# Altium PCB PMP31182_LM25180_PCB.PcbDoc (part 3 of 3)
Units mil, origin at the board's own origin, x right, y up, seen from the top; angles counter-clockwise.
Board outline 4922 x 2266 mil, 4 copper layers (Top Layer, Signal Layer 1, Signal Layer 2, Bottom Layer), stack 77.9 mil thick; 166 components, 96 nets, 525 pads, 505 vias.

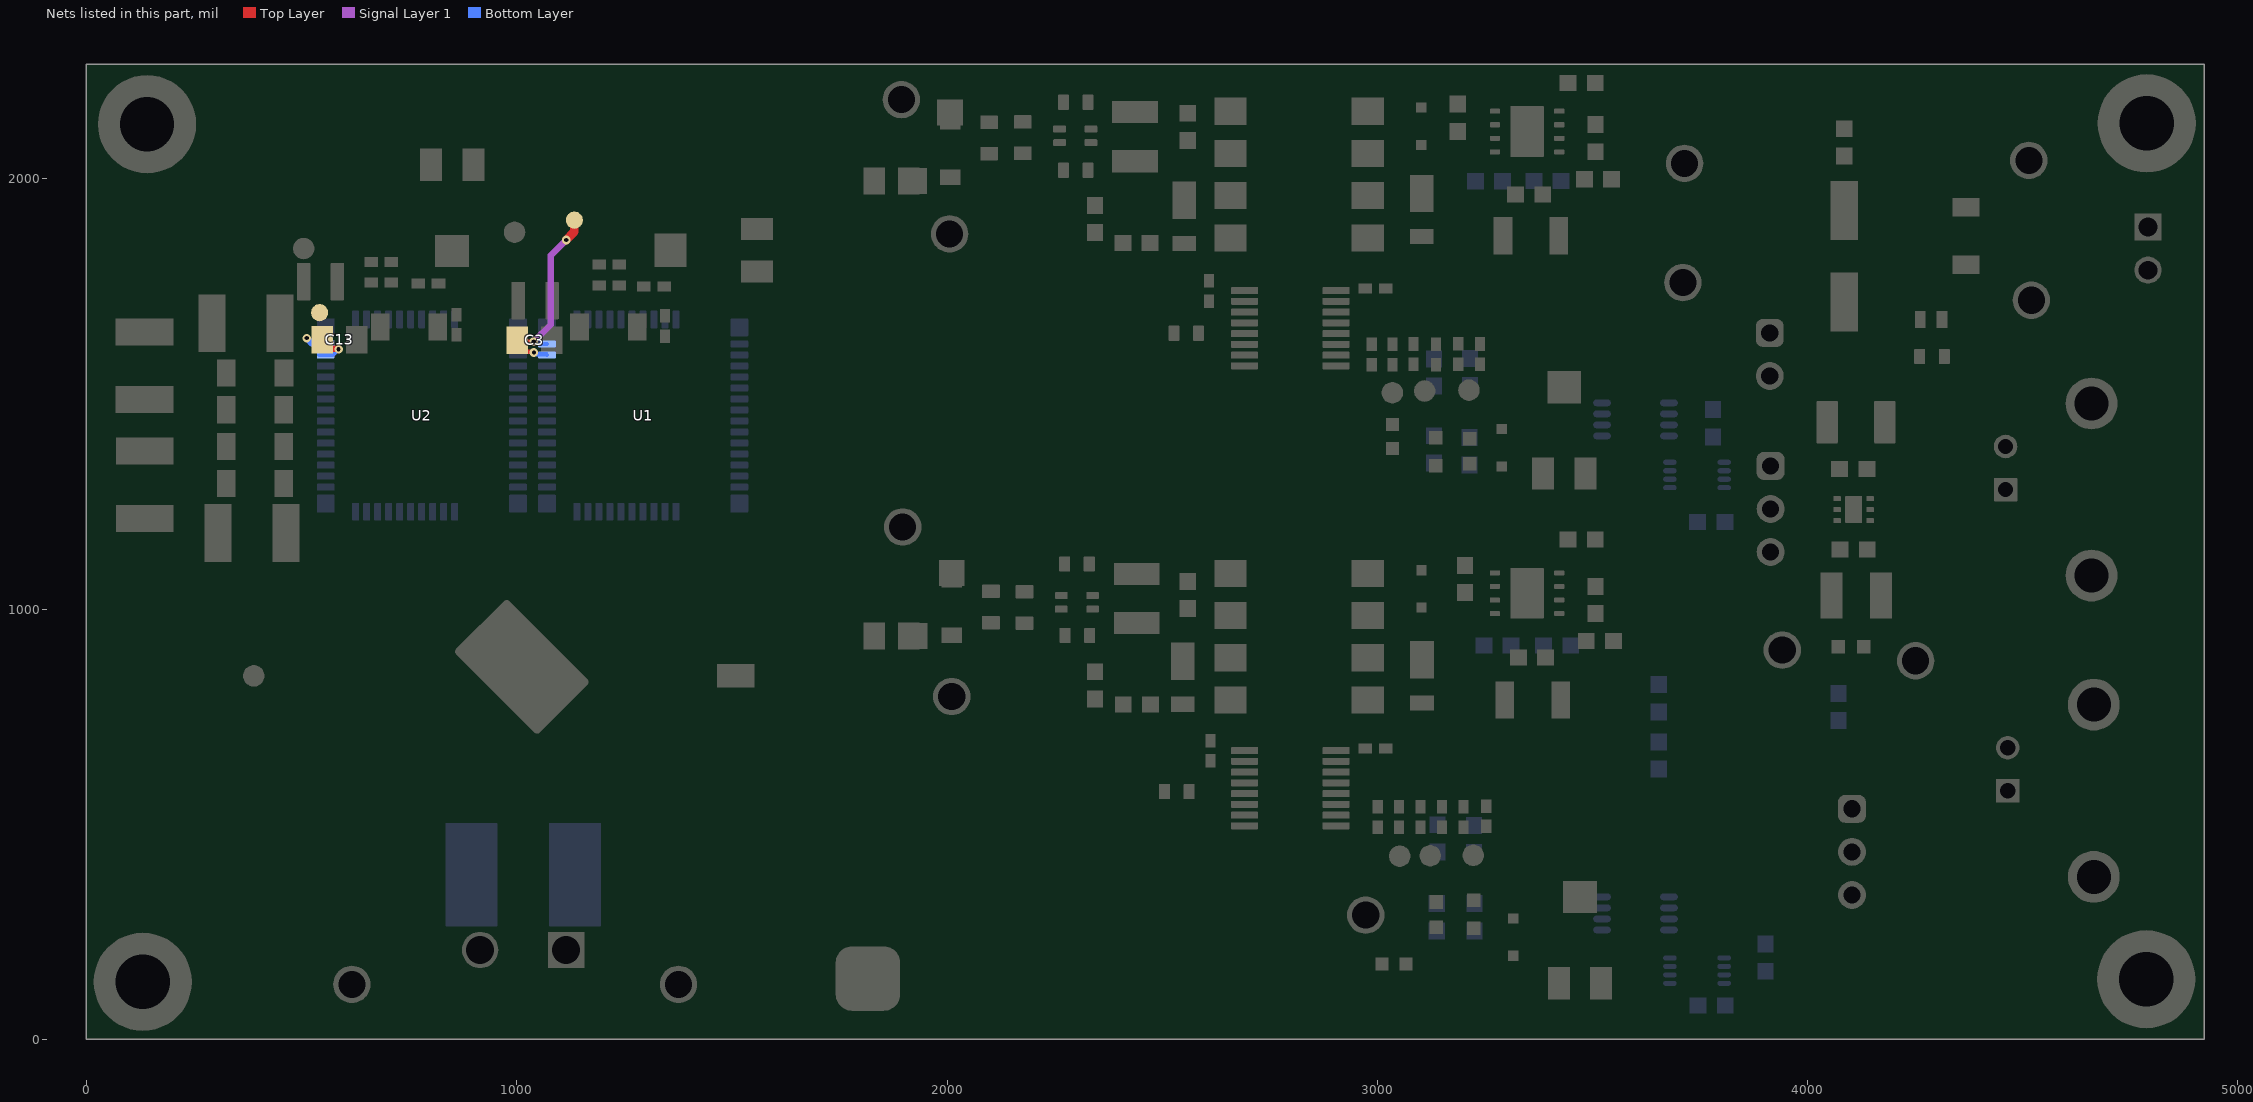
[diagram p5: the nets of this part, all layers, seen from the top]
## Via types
v1: diameter 20, hole 10, Top Layer to Bottom Layer, tented both sides, 491 vias
v2: diameter 19.68, hole 7.87, Top Layer to Bottom Layer, 10 vias
v3: diameter 47.24, hole 31.5, Top Layer to Bottom Layer, 4 vias

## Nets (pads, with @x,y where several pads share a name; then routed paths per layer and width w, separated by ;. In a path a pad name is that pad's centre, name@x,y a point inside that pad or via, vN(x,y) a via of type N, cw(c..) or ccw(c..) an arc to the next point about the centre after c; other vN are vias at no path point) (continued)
VNEG_H: C3.2 pad.1@1134,1904 U1.40 U1.41 | length 477.5
  Top Layer w10: C3.2@1001,1625 1001,1618.5 1021,1598.5 1035.25,1598.5 1037.29,1596.46 v1(1040,1596.46) ; C3.2@1004,1622 v1(1039.76,1622)
  Top Layer w20: v1(1115,1858) 1134,1877 pad.1@1134,1904
  Signal Layer 1 w15: v1(1039.76,1622) 1079,1661.24 1079,1822 v1(1115,1858)
  Bottom Layer w10: v1(1039.76,1622) 1052.1,1622 1057.78,1616.32 U1.41@1070.58,1616.32 ; v1(1040,1596.46) 1042.71,1596.46 1046.91,1592.26 1069.04,1592.26 U1.40@1070.58,1590.73
VNEG_L: C13.2 pad.1@542,1689 U2.40 U2.41 | length 147.3
  Top Layer w15: C13.2@549,1624 568,1605 v1@587,1605
  Bottom Layer w10: U2.40@541.28,1590.73 U2.40@556.15,1590.73 572.73,1590.73 v1@587,1605
  Bottom Layer w15: v1(512,1630) 525.69,1616.32 U2.41@556.15,1616.32
  other v1: 586,1604
pads on no net: J1.3 J1.4 J4.3 J4.4 R2.3 R5.3 R33.3 R37.3 SH-J1.0 SH-J2.0 SH-J3.0 T1.2 T1.3 T2.2 T2.3 T3.5 T3.7@4107,1213.63 T3.7@4107,1249.06 U5.9@3348,1007.28 U5.9@3348,1066.72 U6.9@3348,2080.28 U6.9@3348,2139.72

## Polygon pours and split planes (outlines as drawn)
GND_LV on Bottom Layer "Signal Layer 1-GND_LV" (solid, pour order 147): 3045,2193 3045,2196 3091,2238 3583,2238 3787,2238 3833,2192 3832,2191 3832,1609 3868,1574 4859,1574 4859,415 4466,22 3172,22 3110,84 3110,269 3005,374 3005,441 2900,441 2898,439 2898,490 2996.53,490 3008,501.47 3008,1242 2937,1242 2936,1241 2934,1243 2934,1310 2987,1310 3008,1331 3008,1487 2977,1518 2977,1743 3045,1811
GND_HV on Bottom Layer "GND_HV_L04_P000" (solid, remove dead copper, pour order 0): 900,1639 893,1646 786,1646 652,1646 580,1574 470,1574 450,1554 450,1154 470,1134 820,1134 900,1214
SW on Bottom Layer "SW_L04_P004" (solid, remove dead copper, pour order 4): 970.29,1674.3 970.29,1165.3 895,1090 895,1069 905,1059 1221,1059 1238.29,1076.29 1238.29,1175.29 1260.89,1197.89 1371,1198 1380,1207 1380,1246 1240,1386 1240,1450.84 1380,1590.84 1380,1636 1370,1646 1131,1646 1100,1615 1100,1583 1091,1574 1032,1574 1024,1582 1024,1673.77 1013.76,1684 980,1684
HVBUS on Bottom Layer "HVBUS_L04_P016" (solid, remove dead copper, pour order 16): 1540,1672.95 1540,1214 1470,1214 1450,1234 1450,1654 1473,1677 1535.95,1677
SW on Signal Layer 2 "SW_L03_P002" (solid, remove dead copper, pour order 2): 2691,653 2713,631 2713,484 2700,471 2475.05,471 1607,1289.18 1607,1637.45 1530.46,1714 1474,1714 1354,1594 984,1594 973,1605 973,1865 1022,1914 1530,1914 1960,1484 2586.56,857.45 2586.56,757.44
HVBUS on Signal Layer 2 "HVBUS_L03_P054" (solid, remove dead copper, pour order 54): 376,22 317.88,64 317.88,192.12 79.88,430.12 79.88,1709.88 95,1725 342,1725 476,1591 476,1530 1406.59,1530 1491.2,1635.68 1531.32,1635.68 1538.88,1628.12 1538.88,1226.88 1525,1213 935,1213 758.88,1036.88 758.88,470.68 763.88,470.68 814.88,419.68 953.88,419.68 953.88,417.99 977.88,393.99 977.88,60 928,22
GND_LV on Signal Layer 2 "Signal Layer 1-GND_LV" (solid, pour order 146): 4759,1574 4859,1474 4859,415 4466,22 3172,22 3110,84 3110,269 3005,374 3005,441 2900,441 2898,439 2898,490 2996.53,490 3008,501.47 3008,1242 2937,1242 2936,1241 2934,1243 2934,1310 2987,1310 3008,1331 3008,1493 2977,1524 2977,1729 3045,1797 3045,2193 3045,2196 3091,2238 3583,2238 3787,2238 3833,2192 3832,2191 3832,1609 3868,1574
GND_HV on Signal Layer 2 "GND_HV_L03_P096" (solid, remove dead copper, pour order 96): 484,1655.47 484,2146 575,2237 2065,2237 2187,2237 2679,1745 2679,1579.01 2643.99,1544 2037,1544 1627,1954 957,1954 920,1917 920,1620 894,1594 545.48,1594
5V on Signal Layer 2 "5V_L03_P136" (solid, pour order 136): 4375.35,797.4 4114.35,797.4 4114.35,944.4 4118.35,948.4 4118.35,1110.4 4118.35,1156.4 4148.35,1186.4 4171.35,1186.4 4171.35,1223.4 4147.69,1247.06 4147.69,1251.4 4137.35,1251.4 4135.35,1253.4 4135.35,1263.4 4153.35,1263.4 4375.35,1263.4
GND_LV on Signal Layer 1 "Signal Layer 1-GND_LV" (solid, pour order 134): 4770,1575 4859,1486 4859,416 4466,23 3172,23 3110,85 3110,270 3005,375 3005,442 2900,442 2898,440 2898,491 2996.53,491 3008,502.47 3008,1243 2937,1243 2936,1242 2934,1244 2934,1311 2987,1311 3008,1332 3008,1488 2977,1519 2977,1744 3045,1812 3045,2194 3045,2197 3091,2239 3583,2239 3787,2239 3833,2193 3832,2192 3832,1610 3868,1575
GND_HV on Signal Layer 1 "GND_HV_L02_P008" (solid, remove dead copper, pour order 8): 1748,312 1748,313 1706,356 1706,1084 1606,1184 1450,1184 1420,1214 1420,1544 1390,1574 500,1574 481,1593 481,1763 470,1774 320,1774 310,1764 310,1674 283,1647 97,1647 70,1620 70,1064 90,1044 730,1044 888,1202 1251,1202 1300,1153 1300,561 1300.32,560.76 1300.32,560.32 1247,507 1099,507 1073,481 1073,50.87 1103.87,20 1922,20 1923,19 1955,51 1955,260 1903,312
GND_HV on Top Layer "Top Layer-GND_HV" (solid, pour order 152): 924,2070 921,2073 877,2073 874,2070 874,1991 cw(c865.01,1990.99) 865,1982 762.87,1982 749,1968.13 749,1778.65 741.06,1770.72 701,1770.72 696.72,1770.72 693,1767 693,1740 704,1729 719,1714 719,1698 712,1691 712,1618 656,1618 653,1621 653,1655 651,1657 607,1657 603,1653 603,1599 608,1594 894,1594 900,1600 900,1644 890,1654 845,1654 840,1659 840,1686 749,1686 737,1698 737,1715.41 787,1745.19 787,1948 911,1948 ccw(c911.01,1960.99) 924,1961
SW on Top Layer "Top Layer-No Net" (solid, pour order 144): 1301,1685 1299,1687 1292.24,1687 1259,1687 cw(c1258.98,1695.8) 1250.18,1695.82 1250.18,1731.5 1257,1738 1308.8,1738 1311,1741 1311,1761.81 1306,1766 1226.81,1766 1223,1762.18 1223,1740 1233.18,1729.82 1233.17,1693.57 1233.17,1682.07 1223,1671.9 1185,1671.9 1177.05,1663.95 1176.73,1618.6 1172,1615.42 1110.58,1615.42 1106.12,1619.88 1106.11,1656.49 1098.12,1669.79 1098.12,1759.88 1096.19,1761.81 1068.81,1761.81 1067,1760 1067,1670.21 1056.12,1656.65 1056.12,1595.32 1069.33,1588.58 1351.95,1588.58 ccw(c1351.95,1596.8) 1360.18,1596.8 1360.18,1646.58 1355.14,1651 1312.11,1651 1301,1661
SW on Top Layer "SW_L01_P145" (solid, pour order 145): 1608.82,1549.61 1644,1584.79 1824.3,1584.7 2286,1123 2286,1088 2271.51,1073.51 2271.51,1043.49 2280,1035 2280,1025 2083,1025 2056.91,1051.09 1889.91,1051.09 1608.82,1332.18
GND_HV on Top Layer "GND_HV_L01_P082" (solid, remove dead copper, pour order 82): 418,1783 426.8,1794 471,1794 481,1784 481,1667 481,1593 550,1524 1309,1524 1391,1442 1391,1216 1446,1161 1629,1161 1705,1085 1705,356 1748,312 1903,312 1955,260 1955,51 1923,19 1922,20 1705,20 1104.63,20 1074,56.55 1074,482 1099,507 1247,507 1299,559 1300,561 1300,1184.41 1254.37,1230.04 916.04,1230.04 790,1104 418,1104
ISO_15V_H on Top Layer "ISO_15V_H_L01_P116" (solid, pour order 116): 1886,970 1898,982 2067.35,982 2227,982 2252,1007 2277,1007 2280,1004 2280,982 2280,959 2287,952 2287,751 2265,729 1906,729 1886,749
GND_LV on Top Layer "GND_LV_L01_P149" (solid, pour order 149): 3900,1495 3900,745 3994,651 4518,651 4534,702 4534,745 4534,1454 4489,1499 3903,1499
NetC11_2 on Top Layer "NETC11_2_L01_P148" (solid, pour order 148): 647,1845 660,1858 660,2076 716,2132 1523,2132 1692,1963 1855,1963 1855,2026 1757,2026 1559,2224 645,2224 585,2164 585,1857 597,1845
NetD2_2 on Top Layer "NETD2_2_L01_P140" (solid, pour order 140): 2453,764 2459,758 2690.27,758 2696,764.3 2696,908 2686,918 2632,918 2622,908 2622,806 2621,806 2612,797 2461.7,797 2453,788
NetD7_2 on Top Layer "NETD7_2_L01_P141" (solid, pour order 141): 2611,1869 2622,1879 2622,1982 2632,1992 2686,1992 2696,1982 2696,1841.5 2687.36,1832 2459,1832 2453,1838 2453,1865.46 2456.54,1869
GND_LV on Top Layer "GND_LV_L01_P139" (solid, pour order 139): 3117.25,639.25 3126,648 3126,695 3117.75,703.25 3019,703.25 3004,688.25 3004,662.22 2996.03,654.25 2925,654.25 2925,639.25
GND_LV on Top Layer "GND_LV_L01_P138" (solid, pour order 138): 3104,1708 3114,1718 3114,1759 3101,1772 3019,1772 3004,1757 3004,1730.97 2996.03,1723 2925,1723 2925,1708
GND_LV on Top Layer "Top Layer-GND_LV" (solid, pour order 114): 3939.55,2067.55 3965,2094 4250,2094 4489,1855 4846,1855 4858,1867 4858,1956 4827.7,1986.3 4674,1986.3 4637.3,2023 4638,2023 4638,2222 4621.71,2238.29 3934.27,2237.73 3934,2238 3570,2238 3553,2221 3553,2039 3541,2027 3524,2027 3519,2022 3519,1976.46 3507.54,1965 3450.19,1965 3387,2028.19 3387,2075 3379,2083 3318,2083 3309,2074 3309,2016 3314,2011 3348,2011 3364,1994.46 3364,1840 3381,1823 3493,1823 3512,1842 3583,1913 3925,1913 3939.55,1927.55
15V on Top Layer "15V_L01_P104" (solid, pour order 104): 4846,1821 4859,1807 4859,1576 4846,1563 4312,1563 4300,1575 4300,1812 4309,1821
5V on Top Layer "5V_L01_P118" (solid, pour order 118): 4345,1263 4375,1233 4376,1231 4376,822 4351,797 4136,797 4115,818 4115,944 4144,973 4144,1085 4119,1110 4119,1156 4149,1186 4172,1186 4172,1227.34 4148.34,1251 4138,1251 4136,1253 4136,1263
ISO_15V_H_B on Top Layer "ISO_15V_H_B_L01_P115" (solid, pour order 115): 2318.64,847.36 2332,834 2589,834 2589,1021 2553,1021 2525,993 2388,993 2374,1007 2326,1007 2324,1005 2324,954.6 2319.2,949.8
ISO_RET_H_B on Top Layer "ISO_RET_H_B_L01_P117" (solid, pour order 117): 2688,1146 2698,1136 2698,951 2691,944 2633,944 2622,955 2622,1045 2374,1045 2352,1023 2331,1023 2324,1030 2324,1078 2318,1084 2318,1137 2327,1146
ISO_15V_L on Top Layer "ISO_15V_L_L01_P113" (solid, pour order 113): 2248,2092 2231,2075 2080,2075 2031,2026 1886,2026 1886,1845 1912,1819 2274,1819 2284,1829 2284,2030 2276.5,2037.5 2276.5,2038 2276.5,2079.5 2276.5,2089.5 2274,2092
GND_HV on Top Layer "GND_HV_L01_P112" (solid, pour order 112): 2271,2108 2276,2113 2276,2155 2283,2162 2283,2194 2283,2238 1734,2238 1734,2184 1803,2115 2076,2115 2241,2115 2248,2108
ISO_15V_L_B on Top Layer "ISO_15V_L_B_L01_P111" (solid, pour order 111): 2315,1932 2328,1919 2574,1919 2578,1923 2578,2104 2573,2109 2541,2109 2499,2067 2384,2067 2359,2092 2322,2092 2319,2089 2319,2046 2315,2037.2
GND_LV on Top Layer "GND_LV_L01_P110" (solid, pour order 110): 3456,2244.5 3463,2237.5 3463,2237 3463,2163 3451,2151 3309,2151 3309,2235 3318.5,2244.5
GND_LV on Top Layer "GND_LV_L01_P109" (solid, pour order 109): 3453,1078 3463,1088 3463,1202 3456,1209 3318,1209 3309,1199 3309,1083 3314,1078
GND_LV on Top Layer "GND_LV_L01_P108" (solid, pour order 108): 3370,782 3406,746 3406,745 3557,745 3586,774 3586,946 3581,951 3535,951 3529,945 3529,890 3522,883 3424,883 3424,942 3387,979 3387,998 3383,1003 3314,1003 3309,997 3309,963.52 3316.23,956.29 3340.71,956.29 3370,927
NetD5_2 on Top Layer "NETD5_2_L01_P107" (solid, pour order 107): 3278,1078 3284,1084 3285,1085 3285,1203 3277,1211 2961,1211 2958,1211 2940,1193 2940,1069 2940,1064 2953,1051 3103,1051 3133.5,1078
NetD10_2 on Top Layer "NETD10_2_L01_P106" (solid, pour order 106): 2940,2130.5 2945,2125.5 3109,2125.5 3135,2151.5 3280,2151.5 3285,2156.5 3285,2234.5 3275,2244.5 2953,2244.5 2940,2231.5
15V_F on Top Layer "Top Layer-15V_F" (solid, pour order 105): 3248,987.85 3263.35,1015 3285,1015 3285,1027 3284,1028 3248.32,1028 3213,978.5 3166.5,978.5 3152,964 3152,822 2939,822 2936,819 2936,741 2955,722 3143,722 3395,470 3790,470 3817,505.67 3817,1580 3818,1580 3850,1610 3939,1610 3988,1561 4264,1561 4275.44,1572.44 4275.44,1797.56 4268,1805 3633,1805 3591,1805 3557,1771 3362,1771 3341,1792 3341,1986 3331.44,1995.56 3238,1995.56 3238,2061 3266,2089 3283,2089 3285,2091 3285,2100 3284,2101 3278,2101 3244,2101 3198,2055 3168,2055 3156,2043 3156,1902 3150,1896 2942,1896 2932,1886 2932,1804 2944,1792 3127,1792 3309,1610 3574,1610 3623,1561 3623,939 3624,938 3622.73,936.73 3622.73,747.01 3564.72,689 3399.5,689 3348,740.5 3348,908 3343,913 3259.97,913 3248,926.68
VNEG_L on Top Layer "VNEG_L_L01_P097" (solid, remove dead copper, pour order 97): 579,1594 586,1601 586,1615 575,1626 575,1674 567,1682 567,1698 554,1711 536,1711 500,1675 500,1600 506,1594
SW on Top Layer "SW_L01_P088" (solid, remove dead copper, pour order 88): 975,1170 810,1005 810,644 830,624 1210,624 1238.29,652.29 1238.29,1159.71 1228,1170
HVBUS on Top Layer "HVBUS_L01_P032" (solid, remove dead copper, pour order 32): 60,462 60,1234 70,1244 250,1244 270,1264 270,1584 250,1604 70,1604 60,1614 60,1720 74,1734 340,1734 350,1724 350,1062 368,1044 700,1044 740.14,1003.86 740.14,559 793,508 935,508 959,484 959,59 921,21 343.14,21 308,66.61 308,214
GND_HV on Top Layer "GND_HV_L01_P030" (solid, remove dead copper, pour order 30): 70,1524 60,1514 60,1344 70,1334 201,1334 208,1341 208,1514 198,1524
ISO_RET_L_B on Top Layer "ISO_RET_L_B_L01_P028" (solid, pour order 28): 2320,2161 2315,2166 2315,2229 2325,2239 2684,2239 2696,2227 2696,2035 2689,2028 2628,2028 2622,2034 2622,2126 2615,2133 2541,2133 2537,2129 2369,2129 2348,2108 2325,2108 2320,2113

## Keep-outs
Keep-Out Layer:
  lines w10: 2136.71,2261 2141.71,2266 4922,2266 4922,0 3006,0
  text ".Layer_Name" at 502,-792.77 h30

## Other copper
Signal Layer 1:
  pour cut-out: 267,1132.33 267,1164.5 244.91,1178 130.3,1178 111.84,1162.73 111.84,1135 133.17,1119 162.28,1119 247,1119
  pour cut-out: 266,1227.07 306,1227.07 316,1241 316,1578.62 302.49,1595.51 269.25,1595.51 257,1579.17 257,1526.56 257,1241.86
Signal Layer 2:
  pour cut-out: 536,1336 546,1346 546,1411.23 538.99,1420 481.25,1420 473,1409 473,1348.18 480.88,1336
  pour cut-out: 534,1125 546,1137 546,1202.23 537.39,1213 482.75,1213 472,1198.67 472,1140.73 482.18,1125
  pour cut-out: 534,1227 547,1240 547,1302.98 537.39,1315 482.75,1315 473,1302 473,1241.18 482.18,1227
  pour cut-out: 536,1443 547,1454 547,1516.98 538.99,1527 481.25,1527 472,1514.67 472,1456.73 480.88,1443
  pour cut-out: 108,1399 119,1388 200.75,1388 212,1397 212,1454.75 197,1466 124.73,1466 108,1455.18

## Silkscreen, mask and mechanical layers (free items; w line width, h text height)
Top Overlay:
  lines w10: 556,1866 556,1884 557,1885 ; 577,1885 557,1885 ; 623,1819 557,1885 ; 3085,1652 3085,1689 3159,1763 ; 3140,1763 3158,1763 ; 3159,1746 3159,1760
  text "-" at 4727.87,1978 h150 r90
  text "+" at 4658,1621.5 h150
  text "PWM BOT" at 4349.35,1231 h60 r90
  text "PWM TOP" at 4352.02,477 h60 r90
  text "Load_GND" at 1694,241.99 h60
  text "Max DC Input:  / 520 V/25 A" at 804,44 h60
  text "PMP31182_LM25180-Q1" at 3571,16 h60
Bottom Overlay:
  text "Max DC Input:  / 520 V/25 A" at 1371,45 h30
Top Paste:
  text ".Layer_Name" at 5093,3542.51 h30
Bottom Paste:
  text ".Layer_Name" at 5093,3542.51 h30
Top Solder:
  text ".Layer_Name" at 5093,3542.51 h30
Bottom Solder:
  text ".Layer_Name" at 5093,3542.51 h30
M1 Board Outline:
  the board outline again, w15
  text ".Layer_Name" at 502,-792.77 h30
M2 Board Dimensions:
  rectangle: -70,-219.27 55,-94.27
  rectangle: 50,-344.77 425,-219.77
  lines w7: -75,-94.77 -75,-344.77 925,-344.77 925,-94.77 ; -70,-219.27 930,-219.27 ; -70,-94.27 930,-94.27 ; 50,-344.77 50,-94.77 ; 175,-344.77 175,-94.77 ; 425,-344.77 425,-94.77 ; 675,-344.77 675,-94.77
  lines w10: -14.57,3 2986.43,3 ; 0,604 0,2266 4922,2266 4922,0 3624,0 3619,5
  text ".Layer_Name" at 502,-792.77 h30
M3 3D STEP Top:
  lines w10: 0,9 0,2266 4922,2266 4922,9 0,9
  text ".Layer_Name" at 502,-792.77 h30
M4 3D STEP Bottom:
  lines w10: 588.72,2260 583.69,2256.46 208.56,2256.46 0,2139.46 0,0 4922,0 4922,2266 2136.21,2266 2130.21,2260 ; 524,1188 1550,1188 1550,1730 524,1730 524,1188
M5 Assembly Top:
  lines w10: -367,-864.44 6233,-864.44 ; -367,-661.11 6235,-661.11 ; -367,-457.77 -367,-1067.77 3638,-1067.77 6235,-1067.77 6235,-457.77 -366.5,-457.77 -366.5,-1067.77 ; 2098,-1067.77 2098,-457.77 ; 3365,-661.11 3365,-457.77 ; 4205,-661.11 4205,-457.77 ; 4224.5,3267.5 5800,3267.5 ; 4827,-1074.27 4827,-871.44
  text "PCB VIEWED FROM TOP SIDE" at 4287.5,3745.33 h30
  text "IGNORE ->" at 4287.5,3542.51 h30
  text "PLOT NAME =" at 4287.5,3336.67 h30
  text "COMPONENTS MARKED 'DNP' SHOULD NOT BE POPULATED." at 1078.5,-252.77 h30
  text "ASSEMBLY VARIANT:" at 1078,-368.27 h30
  text ".VariantName" at 2114,-368.27 h30
  text "BOARD #:" at 2173,-589.94 h30
  text ".PRJ_Number" at 2718.5,-589.94 h30
  text "REV:" at 3563,-589.94 h30
  text ".PCB_Rev" at 3854.5,-589.94 h30
  text "SVN REV:" at 4401,-589.94 h30
  text ".VersionControl_RevNumber" at 4907,-589.94 h30
  text ".plot_File_Name" at 502,-998.61 h30
  text "GENERATED    :" at 2175,-998.61 h30
  text ".Print_Date" at 3044.5,-998.61 h30
  text ".Print_Time" at 3773.5,-998.61 h30
  text "TEXAS INSTRUMENTS" at 5038,-998.61 h30
M6 Assembly Bottom:
  lines w10: -367.5,-661.61 6234.5,-661.61 ; -365.5,-864.94 6234.5,-864.94 ; 1662.5,-661.61 1662.5,-458.27 ; 2502.5,-661.61 2502.5,-458.27 ; 3769.5,-1068.27 3769.5,-458.27 ; 4658.5,-1068.27 6234,-1068.27 6234,-458.27 -367.5,-458.27 -367.5,-1068.27 2229.5,-1068.27 6234.5,-1068.27 6234.5,-458.27 ; 5631.5,3260.5 5631.5,3463.33
  text ".VersionControl_RevNumber" at 5551.5,3744.83 h30
  text "TEXAS INSTRUMENTS" at 5420.5,3336.17 h30
  text "COMPONENTS MARKED 'DNP' SHOULD NOT BE POPULATED." at 6724,-256.27 h30
  text ".VariantName" at 5680,-372.27 h30
  text "ASSEMBLY VARIANT:" at 6719,-372.27 h30
  text "SVN REV:" at 1466.5,-590.44 h30
  text ".PCB_Rev" at 2013,-590.44 h30
  text "REV:" at 2304.5,-590.44 h30
  text ".PRJ_Number" at 3149,-590.44 h30
  text "BOARD #:" at 3694.5,-590.44 h30
  text "PCB VIEWED FROM BOTTOM SIDE" at 6171,-590.44 h30
  text "IGNORE ->" at 2472.85,-792.77 h30
  text ".Print_Time" at 2094,-999.11 h30
  text ".Print_Date" at 2823,-999.11 h30
  text "GENERATED    :" at 3692.5,-999.11 h30
  text ".plot_File_Name" at 5365.5,-999.11 h30
  text "PLOT NAME =" at 6171,-999.11 h30
M9 Title Sheet:
  drawing of 57 lines, arcs and shapes, not listed
  text "1" at 664.84,8102.23 h30
  text "2" at 3160.5,8102.23 h30
  text "3" at 5649.84,8102.23 h30
  text "4" at 8156.51,8102.23 h30
  text "5" at 10655.5,8102.23 h30
  text "6" at 13160.5,8102.23 h30
  text "A" at -491.5,6959.23 h30
  text "A" at 14308.5,6959.23 h30
  text "B" at -491.5,4579.23 h30
  text "B" at 14308.5,4579.23 h30
  text "1" at 5255.84,3137.5 h30
  text "C" at 14308.5,2204.23 h30
  text "PROJECT TITLE:" at 11268.5,343.23 h30
  text "LMG342xRx0" at 11318.5,209.9 h30
  text "DESIGNED FOR:" at 11268.5,42.23 h30
  text ".PRJ_Customer" at 11318.5,-97.77 h30
  text "D" at -491.5,-165.77 h30
  text "D" at 14308.5,-165.77 h30
  text "FILE NAME:" at 11268.5,-257.77 h30
  text ".PCB_File_Name_No_Path" at 11318.5,-377.77 h30
  text "Texas Instruments (TI) and/or its licensors do not warrant the accuracy or completeness of this specification" at 6299,-539.61 h30
  text "ENGINEER:" at 11268.5,-547.77 h30
  text "LAYOUT BY:" at 12773.5,-547.77 h30
  text "or any information contained therein. TI and/or its licensors do not warrant that this design will meet" at 6254.02,-652.28 h30
  text "Rui Gao" at 11318.5,-702.77 h30
  text "Rui Gao" at 12824,-702.77 h30
  text "the specifications, will be suitable for your application or fit for any particular purpose, or will operate in" at 6254.02,-764.94 h30
  text ".Layer_Name" at 502,-792.77 h30
  text "ALTIUM DESIGNER VERSION:" at 12773.5,-857.77 h30
  text "an implementation. TI and/or its licensors do not warrant that the design is production worthy. You should" at 6254.02,-877.61 h30
  text "completely validate and test your design implementation to confirm the system functionality for your application." at 6299,-990.27 h30
  text ".print_Scale" at 11318.5,-991.1 h30
  text ".Application_BuildNumber" at 12824,-991.1 h30
  text "2" at 3160.5,-1197.77 h30
  text "3" at 5649.84,-1197.77 h30
  text "4" at 8156.51,-1197.77 h30
  text "5" at 10655.5,-1197.77 h30
  text "6" at 13160.5,-1197.77 h30
M10 Fab Notes:
  drawing of 185 lines, arcs and shapes, not listed
  text "DESIGN INFORMATION" at 12306.02,5975.73 h30
  text "MIN. TRACK WIDTH:" at 11661.46,5795.73 h30
  text "6" at 12757.7,5795.73 h30
  text "MIL" at 12912.46,5795.73 h30
  text "MIN. CLEARANCE:" at 11661.46,5663.73 h30
  text "5.5" at 12697.7,5663.73 h30
  text "MIL" at 12912.46,5663.73 h30
  text "MIN. VIA PAD SIZE:" at 11661.46,5531.73 h30
  text "16" at 12727.71,5531.73 h30
  text "MIL" at 12912.46,5531.73 h30
  text "4 MIL" at 12356.46,5390.01 h30
  text "MINIMUM ANNULAR RING" at 11332.23,5385.73 h30
  text "PER" at 11532.23,5267.73 h30
  text "IPC-D-275 CLASS 2 LEVEL C" at 11752.23,5267.73 h30
  text "MIL, HOLES" at 13240.46,5155.44 h30
  text "+/-" at 12848,5154.73 h30
  text "+/-" at 13702,5154.73 h30
  text "REGISTRATION TOLERANCES:" at 11332.23,5149.73 h30
  text "METAL" at 12532,5149.73 h30
  text "MIL" at 14057.46,5149.73 h30
  text "MATERIAL:" at 11257.46,4940.27 h30
  text "FR-4 High Tg" at 12243.9,4799.93 h30
  text "FR-408" at 11678.46,4791.36 h30
  text "X" at 12090.46,4791.36 h30
  text "OTHER" at 13166.46,4791.36 h30
  text "X" at 11877.46,4636.36 h30
  text "78.7 MIL (2.0 mm) +/-10%" at 11998.56,4628.65 h30
  text "THICKNESS:" at 11332.23,4624.36 h30
  text "OTHER" at 13283.46,4624.36 h30
  text "TOLERANCE:" at 11332.23,4466.36 h30
  text "X" at 12171.54,4466.36 h30
  text "ANSI IPC-6012 TYPE 3 CLASS 2" at 12358.48,4466.36 h30
  text "OTHER +/-" at 12358.46,4310.36 h30
  text "BOW & TWIST:" at 11332.23,4153.36 h30
  text "X" at 12171.54,4153.36 h30
  text "ANSI IPC-6012 TYPE 3 CLASS 2" at 12358.48,4153.36 h30
  text "OTHER +/-" at 12358.46,3994.86 h30
  text "DRILLING:" at 11257.46,3856.36 h30
  text "REFERENCE:" at 11332.23,3739.36 h30
  text "X" at 11980.46,3739.36 h30
  text "AS SHOWN" at 12167.46,3739.36 h30
  text "X" at 12881.46,3739.36 h30
  text "NC_DRILL FILES" at 13018.46,3739.36 h30
  text "PTH MIN COPPER THICKNESS:" at 11332.23,3581.36 h30
  text "X" at 12674.46,3581.36 h30
  text "1MIL" at 12819.46,3581.36 h30
  text "OTHER" at 13316.46,3581.36 h30
  text "BOARD FINISH:" at 11257.46,3422.36 h30
  text "SILKSCREEN:" at 11412.68,3304.36 h30
  text "X" at 12361.46,3304.36 h30
  text "TOP" at 12487.46,3304.36 h30
  text "X" at 12871.46,3304.36 h30
  text "BOTTOM" at 12998.46,3304.36 h30
  text "SILKSCREEN COLOR:" at 11412.68,3137.36 h30
  text "X" at 12360.42,3137.36 h30
  text "WHITE" at 12487.46,3137.36 h30
  text "OTHER" at 12998.46,3137.36 h30
  text "SOLDER RESIST COLOR:" at 11412.68,2967.36 h30
  text "X" at 11980.42,2808.17 h30
  text "GREEN" at 12107.46,2808.17 h30
  text "BLUE" at 12698.46,2808.17 h30
  text "OTHER" at 13236.46,2808.17 h30
  text "IMMERSION GOLD (ENIG)" at 12318.46,2619.65 h30
  text "ENEPIG" at 13656,2616.36 h30
  text "SURFACE FINISH:" at 11257.46,2615.36 h30
  text "X" at 12131.51,2615.36 h30
  text "IMM. TIN/SILVER OR EQUIV" at 11587,2458.36 h30
  text "OTHER" at 13018.46,2458.36 h30
  text "X" at 12134,2287 h30
  text "ARRAY/PANEL:" at 11257.46,2279.36 h30
  text "CUT AND TRIM PER MECH LAYER 1" at 12318.46,2275.08 h30
  text "N.C. ROUTE" at 12318.46,2123.36 h30
  text "V. SCORE" at 13184.46,2123.36 h30
  text "CERTIFICATION:" at 11257.46,1986.36 h30
  text "MATERIALS AND WORKMANSHIP FOR ALL PCBS" at 11982.46,1986.36 h30
  text "TO MEET OR EXCEED THE REQUIREMENTS OF:" at 11982.46,1888.36 h30
  text "X" at 11608.96,1751.86 h30
  text "ANSI IPC-A-600F CLASS ->" at 11747.96,1751.86 h30
  text "X" at 13387.02,1751.86 h30
  text "2" at 13505.96,1751.86 h30
  text "1" at 13190.96,1750.36 h30
  text "3" at 13859.96,1750.36 h30
  text "X" at 11611.02,1592.36 h30
  text "UL 94V-0" at 11747.96,1592.36 h30
  text "X" at 12423.02,1592.36 h30
  text "RoHS" at 12559.96,1592.36 h30
  text "OTHER" at 13204.37,1592.36 h30
  text "PER ORDER" at 13601.42,1592.36 h30
  text "ADDITIONAL REQUIREMENTS:" at 11257.46,1451.36 h30
  text "MICROSECTION:" at 11332.23,1336.36 h30
  text "YES" at 12237.96,1336.36 h30
  text "REQUIRED" at 13099.46,1180.22 h30
  text "BARE BOARD ELEC. TEST:" at 11332.23,1177.36 h30
  text "NONE" at 12637.96,1177.36 h30
  text "X" at 12972.46,1177.36 h30
  text "PER ORDER" at 13691.46,1177.36 h30
  text "MANUFACTURER'S UL:" at 11332.23,1020.36 h30
  text "RAIL" at 12497.96,1016.08 h30
  text "METAL" at 12989.78,1016.08 h30
  text "X" at 13365,1015.73 h30
  text "SILK" at 13501.46,1016.08 h30
  text ".Layer_Name" at 502,-792.77 h30
M11 Gerber Information:
  lines w10: -367,-864.44 6233,-864.44 ; -367,-661.11 6235,-661.11 ; -367,-457.77 -367,-1067.77 3638,-1067.77 6235,-1067.77 6235,-457.77 -366.5,-457.77 -366.5,-1067.77 ; 2098,-1067.77 2098,-457.77 ; 3365,-661.11 3365,-457.77 ; 4205,-661.11 4205,-457.77 ; 4224.5,3267.5 5800,3267.5 ; 4827,-1074.27 4827,-871.44
  text "PLOT NAME =" at 4287.5,3336.67 h30
  text "BOARD #:" at 2173,-589.94 h30
  text ".PRJ_Number" at 2718.5,-589.94 h30
  text "REV:" at 3563,-589.94 h30
  text ".PCB_Rev" at 3854.5,-589.94 h30
  text "SVN REV:" at 4401,-589.94 h30
  text ".VersionControl_RevNumber" at 4907,-589.94 h30
  text ".plot_File_Name" at 502,-998.61 h30
  text "GENERATED    :" at 2175,-998.61 h30
  text ".Print_Date" at 3044.5,-998.61 h30
  text ".Print_Time" at 3773.5,-998.61 h30
  text "TEXAS INSTRUMENTS" at 5038,-998.61 h30
M12 Stackup:
  drawing of 295 lines, arcs and shapes, not listed
  text "Layer" at 9552.84,7738.23 h60
  text "Name" at 9962.76,7738.23 h60
  text "Material" at 10902.5,7738.23 h60
  text "Thickness" at 11762.26,7738.23 h60
  text "Constant" at 12412.1,7738.23 h60
  text "Board Layer Stack" at 12981.96,7738.23 h60
  text "Top Overlay" at 9962.76,7618.23 h60
  text "Top Solder" at 9962.76,7498.23 h60
  text "Solder Resist" at 10902.5,7498.23 h60
  text "0.40mil" at 11762.26,7498.23 h60
  text "3.5" at 12412.1,7498.23 h60
  text "1" at 9552.84,7378.23 h60
  text "Top Layer" at 9962.76,7378.23 h60
  text "2.80mil" at 11762.26,7378.23 h60
  text "Dielectric 1" at 9962.76,7258.23 h60
  text "FR-4" at 10902.5,7258.23 h60
  text "4.60mil" at 11762.26,7258.23 h60
  text "4.2" at 12412.1,7258.23 h60
  text "2" at 9552.84,7138.23 h60
  text "Signal Layer 1" at 9962.76,7138.23 h60
  text "2.80mil" at 11762.26,7138.23 h60
  text "Dielectric 2" at 9962.76,7018.23 h60
  text "FR-4" at 10902.5,7018.23 h60
  text "57.50mil" at 11762.26,7018.23 h60
  text "4.2" at 12412.1,7018.23 h60
  text "3" at 9552.84,6898.23 h60
  text "Signal Layer 2" at 9962.76,6898.23 h60
  text "2.80mil" at 11762.26,6898.23 h60
  text "Dielectric 3" at 9962.76,6778.23 h60
  text "FR-4" at 10902.5,6778.23 h60
  text "4.60mil" at 11762.26,6778.23 h60
  text "4.2" at 12412.1,6778.23 h60
  text "4" at 9552.84,6658.23 h60
  text "Bottom Layer" at 9962.76,6658.23 h60
  text "2.80mil" at 11762.26,6658.23 h60
  text "Bottom Solder" at 9962.76,6538.23 h60
  text "Solder Resist" at 10902.5,6538.23 h60
  text "0.40mil" at 11762.26,6538.23 h60
  text "3.5" at 12412.1,6538.23 h60
  text "Bottom Overlay" at 9962.76,6418.23 h60
  text ".Layer_Name" at 5093,3542.51 h30
M13 Component Bodies Top:
  text ".Layer_Name" at 502,-792.77 h30
M14 Component Bodies Bottom:
  text ".Layer_Name" at 502,-792.77 h30
M15 Courtyards Top:
  text ".Layer_Name" at 502,-792.77 h30
M16 Courtyards Bottom:
  text ".Layer_Name" at 502,-792.77 h30
Drill Drawing:
  circle w10: c6502.89,409.18 r23.04
  lines w10: 6479.85,86.62 6491.37,86.62 6502.89,75.1 6514.41,86.62 6525.93,86.62 6514.41,98.14 6525.93,109.66 6514.41,109.66 6502.89,121.18 6491.37,109.66 6479.85,109.66 6491.37,98.14 6479.85,86.62 ; 6479.85,178.78 6479.85,190.3 6491.37,201.82 6479.85,213.34 6479.85,224.86 6491.37,224.86 6502.89,213.34 6514.41,224.86 6525.93,224.86 6525.93,213.34 6514.41,201.82 6525.93,190.3 6525.93,178.78 6514.41,178.78 6502.89,190.3 6491.37,178.78 6479.85,178.78 ; 6479.85,282.46 6525.93,282.46 6525.93,328.54 6479.85,328.54 6479.85,282.46 ; 6479.85,639.59 6525.93,639.59 6502.89,593.51 6479.85,639.59 ; 6479.85,708.71 6491.37,708.71 6491.37,697.19 6514.41,697.19 6514.41,708.71 6525.93,708.71 6525.93,731.75 6514.41,731.75 6514.41,743.27 6491.37,743.27 6491.37,731.75 6479.85,731.75 6479.85,708.71 ; 6479.85,812.39 6491.37,812.39 6491.37,800.87 6514.41,800.87 6514.41,812.39 6525.93,812.39 6525.93,835.43 6514.41,835.43 6514.41,846.95 6491.37,846.95 6491.37,835.43 6479.85,835.43 6479.85,812.39 ; 6479.85,904.55 6479.85,916.07 6491.37,927.59 6479.85,939.11 6479.85,950.63 6491.37,950.63 6502.89,939.11 6514.41,950.63 6525.93,950.63 6525.93,939.11 6514.41,927.59 6525.93,916.07 6525.93,904.55 6514.41,904.55 6502.89,916.07 6491.37,904.55 6479.85,904.55 ; 6479.85,1019.75 6491.37,1019.75 6502.89,1008.23 6514.41,1019.75 6525.93,1019.75 6514.41,1031.27 6525.93,1042.79 6514.41,1042.79 6502.89,1054.31 6491.37,1042.79 6479.85,1042.79 6491.37,1031.27 6479.85,1019.75 ; 6489.06,188 6489.06,194.91 6495.98,201.82 6489.06,208.73 6489.06,215.65 6495.98,215.65 6502.89,208.73 6509.8,215.65 6516.71,215.65 6516.71,208.73 6509.8,201.82 6516.71,194.91 6516.71,188 6509.8,188 6502.89,194.91 6495.98,188 6489.06,188 ; 6489.06,291.68 6516.71,291.68 6516.71,319.33 6489.06,319.33 6489.06,291.68 ; 6489.06,713.32 6495.98,713.32 6495.98,706.4 6509.8,706.4 6509.8,713.32 6516.71,713.32 6516.71,727.14 6509.8,727.14 6509.8,734.05 6495.98,734.05 6495.98,727.14 6489.06,727.14 6489.06,713.32 ; 6489.06,1024.36 6495.98,1024.36 6502.89,1017.45 6509.8,1024.36 6516.71,1024.36 6509.8,1031.27 6516.71,1038.18 6509.8,1038.18 6502.89,1045.1 6495.98,1038.18 6489.06,1038.18 6495.98,1031.27 6489.06,1024.36
  lines w12: 6437.55,44 10686.45,44 ; 6437.55,1080.81 10686.45,1080.81 ; 6828.21,-59.68 6828.21,1184.49 ; 7278.96,-59.68 7278.96,1184.49 ; 8218.94,-59.68 8218.94,1184.49 ; 8578.48,-59.68 8578.48,1184.49 ; 9095.57,-59.68 9095.57,1184.49 ; 10138.25,-59.68 10138.25,1184.49 ; 6437.55,-59.68 10686.45,-59.68 10686.45,1184.49 6437.55,1184.49 6437.55,-59.68
  text ".Layer_Name" at 5093,3542.51 h30
  text "Symbol" at 6499.76,1111.91 h49.77
  text "Quantity" at 6859.31,1111.91 h49.77
  text "Finished Hole Size" at 7310.07,1111.91 h49.77
  text "Plated" at 8250.04,1111.91 h49.77
  text "Hole Type" at 8609.59,1111.91 h49.77
  text "Drill Layer Pair" at 9126.68,1111.91 h49.77
  text "Tolerance" at 10169.36,1111.91 h49.77
  text "10" at 6859.31,1008.23 h41.47
  text "7.87mil (0.200mm)" at 7310.07,1008.23 h41.47
  text "PTH" at 8250.04,1008.23 h41.47
  text "Round" at 8609.59,1008.23 h41.47
  text "Top Layer - Bottom Layer" at 9126.68,1008.23 h41.47
  text "491" at 6859.31,904.55 h41.47
  text "10.00mil (0.254mm)" at 7310.07,904.55 h41.47
  text "PTH" at 8250.04,904.55 h41.47
  text "Round" at 8609.59,904.55 h41.47
  text "Top Layer - Bottom Layer" at 9126.68,904.55 h41.47
  text "4" at 6859.31,800.87 h41.47
  text "31.50mil (0.800mm)" at 7310.07,800.87 h41.47
  text "PTH" at 8250.04,800.87 h41.47
  text "Round" at 8609.59,800.87 h41.47
  text "Top Layer - Bottom Layer" at 9126.68,800.87 h41.47
  text "4" at 6859.31,697.19 h41.47
  text "35.04mil (0.890mm)" at 7310.07,697.19 h41.47
  text "PTH" at 8250.04,697.19 h41.47
  text "Round" at 8609.59,697.19 h41.47
  text "Top Layer - Bottom Layer" at 9126.68,697.19 h41.47
  text "8" at 6859.31,593.51 h41.47
  text "40.00mil (1.016mm)" at 7310.07,593.51 h41.47
  text "PTH" at 8250.04,593.51 h41.47
  text "Round" at 8609.59,593.51 h41.47
  text "Top Layer - Bottom Layer" at 9126.68,593.51 h41.47
  text "2" at 6859.31,489.83 h41.47
  text "43.31mil (1.100mm)" at 7310.07,489.83 h41.47
  text "PTH" at 8250.04,489.83 h41.47
  text "Round" at 8609.59,489.83 h41.47
  text "Top Layer - Bottom Layer" at 9126.68,489.83 h41.47
  text "A" at 6477.53,479.83 h46.08
  text "13" at 6859.31,386.14 h41.47
  text "63.00mil (1.600mm)" at 7310.07,386.14 h41.47
  text "PTH" at 8250.04,386.14 h41.47
  text "Round" at 8609.59,386.14 h41.47
  text "Top Layer - Bottom Layer" at 9126.68,386.14 h41.47
  text "2" at 6859.31,282.46 h41.47
  text "64.96mil (1.650mm)" at 7310.07,282.46 h41.47
  text "PTH" at 8250.04,282.46 h41.47
  text "Round" at 8609.59,282.46 h41.47
  text "Top Layer - Bottom Layer" at 9126.68,282.46 h41.47
  text "4" at 6859.31,178.78 h41.47
  text "79.13mil (2.010mm)" at 7310.07,178.78 h41.47
  text "PTH" at 8250.04,178.78 h41.47
  text "Round" at 8609.59,178.78 h41.47
  text "Top Layer - Bottom Layer" at 9126.68,178.78 h41.47
  text "4" at 6859.31,75.1 h41.47
  text "125.98mil (3.200mm)" at 7310.07,75.1 h41.47
  text "PTH" at 8250.04,75.1 h41.47
  text "Round" at 8609.59,75.1 h41.47
  text "Top Layer - Bottom Layer" at 9126.68,75.1 h41.47
  text "542 Total" at 6859.31,-28.58 h41.47
Bottom Courtyard:
  pour cut-out: 536,1443 544,1451 544,1520.73 538.99,1527 481.25,1527 475,1518.67 475,1452.09 480.88,1443

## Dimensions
0,2266 to 0,0 on M2 Board Dimensions
-75,-344.77 to 925,-344.77 on M2 Board Dimensions
0,0 to 4922,0 on M2 Board Dimensions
